VERSION 5.6 ;

BUSBITCHARS "[]" ;

DIVIDERCHAR "/" ;

UNITS
    DATABASE MICRONS 2000 ;
END UNITS

MANUFACTURINGGRID 0.000500 ; 

CLEARANCEMEASURE EUCLIDEAN ; 

USEMINSPACING OBS ON ; 

SITE CoreSite
    CLASS CORE ;
    SIZE 2.400000 BY 2.400000 ;
END CoreSite

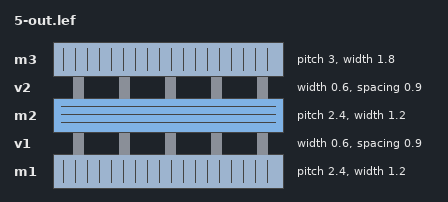
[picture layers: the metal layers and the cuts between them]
LAYER m1
   TYPE ROUTING ;
   DIRECTION VERTICAL ;
   MINWIDTH 1.200000 ;
   AREA 0.810000 ;
   WIDTH 1.200000 ;
   SPACINGTABLE
      PARALLELRUNLENGTH 0.0
      WIDTH 0.0 1.200000 ;
   PITCH 2.400000 2.400000 ;
END m1

LAYER v1
    TYPE CUT ;
    SPACING 0.900000 ;
    WIDTH 0.600000 ;
    ENCLOSURE ABOVE 0.300000 0.300000 ;
    ENCLOSURE BELOW 0.300000 0.300000 ;
END v1

LAYER m2
   TYPE ROUTING ;
   DIRECTION HORIZONTAL ;
   MINWIDTH 1.200000 ;
   AREA 0.810000 ;
   WIDTH 1.200000 ;
   SPACINGTABLE
      PARALLELRUNLENGTH 0.0
      WIDTH 0.0 1.200000 ;
   PITCH 2.400000 2.400000 ;
END m2

LAYER v2
    TYPE CUT ;
    SPACING 0.900000 ;
    WIDTH 0.600000 ;
    ENCLOSURE ABOVE 0.300000 0.300000 ;
    ENCLOSURE BELOW 0.300000 0.300000 ;
END v2

LAYER m3
   TYPE ROUTING ;
   DIRECTION VERTICAL ;
   MINWIDTH 1.800000 ;
   AREA 2.250000 ;
   WIDTH 1.800000 ;
   SPACINGTABLE
      PARALLELRUNLENGTH 0.0
      WIDTH 0.0 1.200000 ;
   PITCH 3.000000 3.000000 ;
END m3

LAYER OVERLAP
   TYPE OVERLAP ;
END OVERLAP

VIA v1_C DEFAULT
   LAYER m1 ;
     RECT -0.600000 -0.600000 0.600000 0.600000 ;
   LAYER v1 ;
     RECT -0.300000 -0.300000 0.300000 0.300000 ;
   LAYER m2 ;
     RECT -0.600000 -0.600000 0.600000 0.600000 ;
END v1_C

VIA v2_C DEFAULT
   LAYER m2 ;
     RECT -0.600000 -0.600000 0.600000 0.600000 ;
   LAYER v2 ;
     RECT -0.300000 -0.300000 0.300000 0.300000 ;
   LAYER m3 ;
     RECT -0.600000 -0.600000 0.600000 0.600000 ;
END v2_C

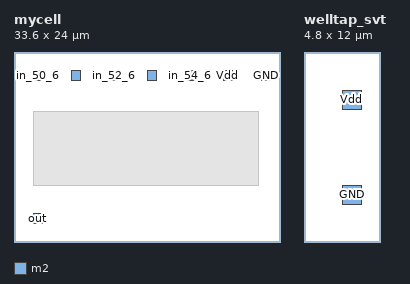
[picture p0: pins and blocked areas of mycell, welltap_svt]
MACRO mycell
    CLASS CORE ;
    FOREIGN mycell 0.000000 0.000000 ;
    ORIGIN 0.000000 0.000000 ;
    SIZE 33.600000 BY 24.000000 ;
    SYMMETRY X Y ;
    SITE CoreSite ;
    PIN in_50_6
        DIRECTION INPUT ;
        USE SIGNAL ;
        PORT
        LAYER m2 ;
        RECT 2.400000 20.400000 3.600000 21.600000 ;
        END
    END in_50_6
    PIN in_51_6
        DIRECTION INPUT ;
        USE SIGNAL ;
        PORT
        LAYER m2 ;
        RECT 7.200000 20.400000 8.400000 21.600000 ;
        END
    END in_51_6
    PIN in_52_6
        DIRECTION INPUT ;
        USE SIGNAL ;
        PORT
        LAYER m2 ;
        RECT 12.000000 20.400000 13.200000 21.600000 ;
        END
    END in_52_6
    PIN in_53_6
        DIRECTION INPUT ;
        USE SIGNAL ;
        PORT
        LAYER m2 ;
        RECT 16.800000 20.400000 18.000000 21.600000 ;
        END
    END in_53_6
    PIN in_54_6
        DIRECTION INPUT ;
        USE SIGNAL ;
        PORT
        LAYER m2 ;
        RECT 21.600000 20.400000 22.800000 21.600000 ;
        END
    END in_54_6
    PIN out
        DIRECTION OUTPUT ;
        USE SIGNAL ;
        PORT
        LAYER m2 ;
        RECT 2.400000 2.400000 3.600000 3.600000 ;
        END
        ANTENNADIFFAREA 11.970000 ;
    END out
    PIN Vdd
        DIRECTION INPUT ;
        USE POWER ;
        PORT
        LAYER m2 ;
        RECT 26.400000 20.400000 27.600000 21.600000 ;
        END
        ANTENNADIFFAREA 7.020000 ;
    END Vdd
    PIN GND
        DIRECTION INPUT ;
        USE GROUND ;
        PORT
        LAYER m2 ;
        RECT 31.200000 20.400000 32.400000 21.600000 ;
        END
        ANTENNADIFFAREA 5.400000 ;
    END GND
    OBS
      LAYER m1 ;
         RECT 2.400000 7.200000 30.900000 16.500000 ;
    END
END mycell

MACRO welltap_svt
    CLASS CORE WELLTAP ;
    FOREIGN welltap_svt 0.000000 0.000000 ;
    ORIGIN 0.000000 0.000000 ;
    SIZE 4.800000 BY 12.000000 ;
    SYMMETRY X Y ;
    SITE CoreSite ;
    PIN Vdd
        DIRECTION INPUT ;
        USE POWER ;
        PORT
        LAYER m2 ;
        RECT 2.400000 8.400000 3.600000 9.600000 ;
        END
    END Vdd
    PIN GND
        DIRECTION INPUT ;
        USE GROUND ;
        PORT
        LAYER m2 ;
        RECT 2.400000 2.400000 3.600000 3.600000 ;
        END
    END GND
END welltap_svt

